VERSION 5.8 ;
BUSBITCHARS "[]" ;
DIVIDERCHAR "/" ;
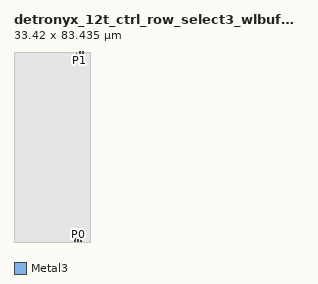
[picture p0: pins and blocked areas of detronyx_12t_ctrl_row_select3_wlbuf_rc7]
MACRO detronyx_12t_ctrl_row_select3_wlbuf_rc7
  CLASS BLOCK ;
  FOREIGN detronyx_12t_ctrl_row_select3_wlbuf_rc7 0.000 0.000 ;
  ORIGIN 0.000 0.000 ;
  SIZE 33.420000 BY 83.435000 ;
  SYMMETRY X Y ;
  PIN VDD
    DIRECTION INOUT ;
    USE POWER ;
    PORT
      LAYER Metal3 ;
        RECT 27.240000 81.735000 27.600000 82.935000 ;
    END
  END VDD
  PIN VSS
    DIRECTION INOUT ;
    USE GROUND ;
    PORT
      LAYER Metal3 ;
        RECT 26.540000 0.200000 26.900000 1.400000 ;
    END
  END VSS
  PIN P0
    DIRECTION INPUT ;
    USE SIGNAL ;
    PORT
      LAYER Metal3 ;
        RECT 27.940000 0.400000 28.300000 1.200000 ;
    END
  END P0
  PIN P1
    DIRECTION INPUT ;
    USE SIGNAL ;
    PORT
      LAYER Metal3 ;
        RECT 28.640000 82.835000 29.000000 83.635000 ;
    END
  END P1
  PIN P2
    DIRECTION INPUT ;
    USE SIGNAL ;
    PORT
      LAYER Metal3 ;
        RECT 29.340000 0.400000 29.700000 1.200000 ;
    END
  END P2
  PIN WL
    DIRECTION OUTPUT ;
    USE SIGNAL ;
    PORT
      LAYER Metal3 ;
        RECT 30.040000 82.835000 30.400000 83.635000 ;
    END
  END WL
  OBS
    LAYER Metal1 ;
      RECT 0.000000 0.000000 33.420000 83.435000 ;
    LAYER Metal2 ;
      RECT 0.000000 0.000000 33.420000 83.435000 ;
  END
END detronyx_12t_ctrl_row_select3_wlbuf_rc7
END LIBRARY
